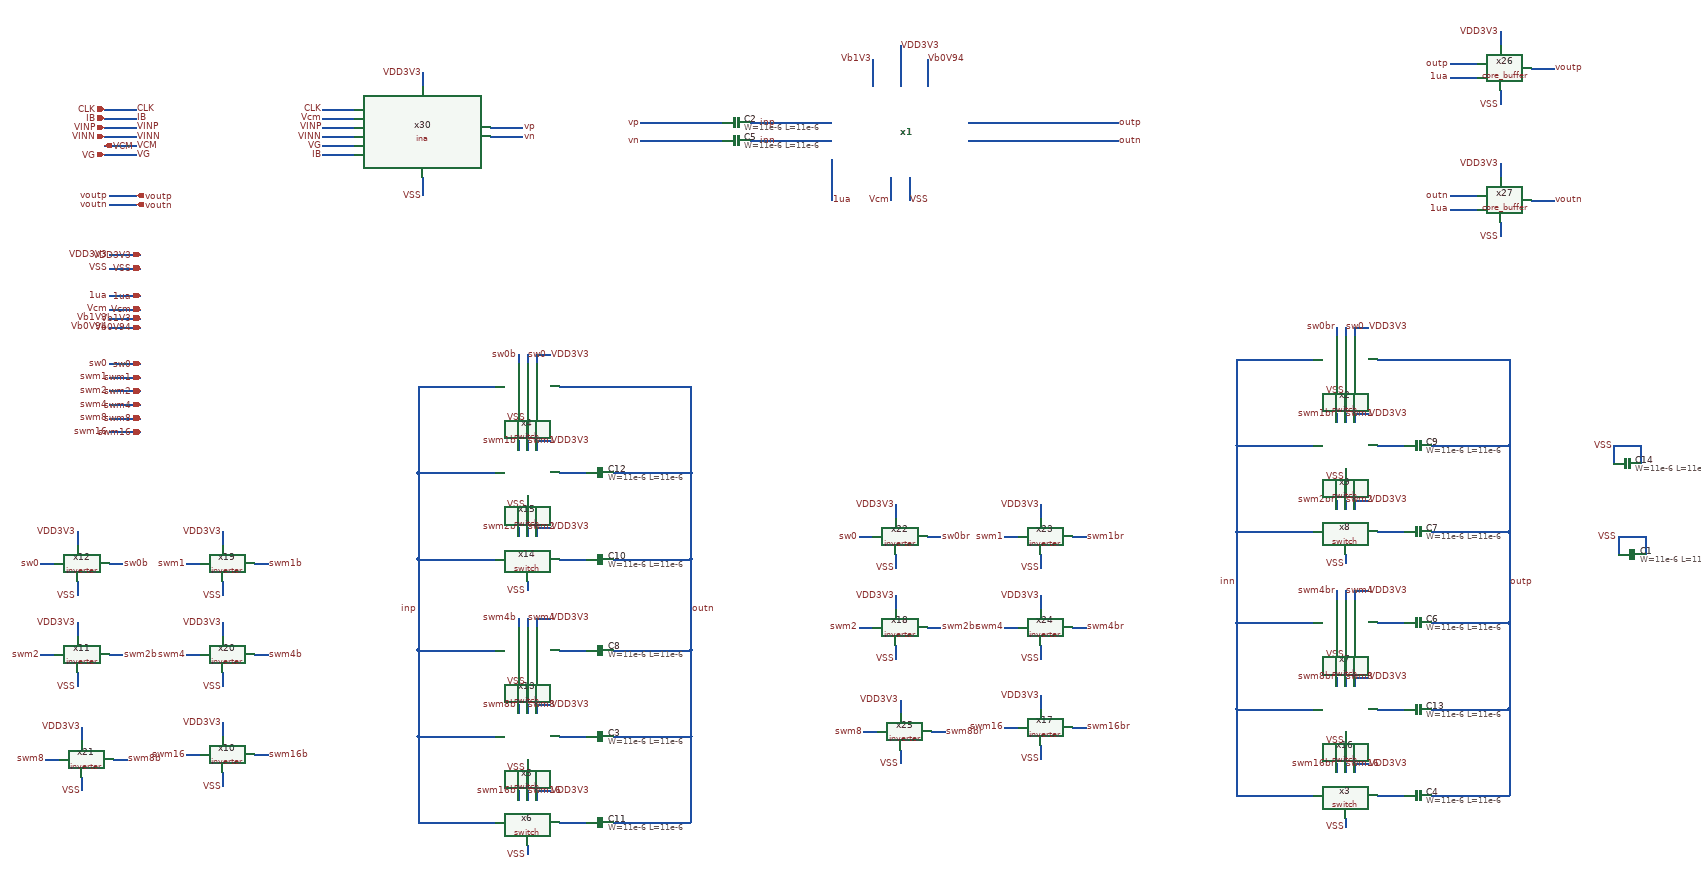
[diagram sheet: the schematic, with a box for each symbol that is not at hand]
v {xschem version=3.4.8RC file_version=1.3}
G {}
K {}
V {}
S {}
F {}
E {}
N 5160 -3050 5160 -3000 {lab=VSS}
N 4810 -3170 4990 -3170 {lab=inp}
N 4810 -3130 4990 -3130 {lab=inn}
N 5140 -3340 5140 -3250 {lab=VDD3V3}
N 5200 -3310 5200 -3250 {lab=Vb0V94}
N 5120 -3050 5120 -3000 {lab=Vcm}
N 5080 -3310 5080 -3250 {lab=Vb1V3}
N 4570 -3170 4750 -3170 {lab=vp}
N 4570 -3130 4750 -3130 {lab=vn}
N 4990 -3090 4990 -3000 {lab=1ua}
N 5290 -3130 5480 -3130 {lab=outn}
N 5290 -3170 5390 -3170 {lab=outp}
N 5390 -3170 5620 -3170 {lab=outp}
N 5480 -3130 5620 -3130 {lab=outn}
N 3400 -2990 3460 -2990 {lab=voutn}
N 3410 -2850 3470 -2850 {lab=VSS}
N 3400 -2850 3410 -2850 {lab=VSS}
N 3410 -2880 3470 -2880 {lab=VDD3V3}
N 3400 -2880 3410 -2880 {lab=VDD3V3}
N 3410 -2790 3470 -2790 {lab=1ua}
N 3400 -2790 3410 -2790 {lab=1ua}
N 3410 -2760 3470 -2760 {lab=Vcm}
N 3400 -2760 3410 -2760 {lab=Vcm}
N 3410 -2740 3470 -2740 {lab=Vb1V3}
N 3400 -2740 3410 -2740 {lab=Vb1V3}
N 3410 -2720 3470 -2720 {lab=Vb0V94}
N 3400 -2720 3410 -2720 {lab=Vb0V94}
N 3400 -3010 3460 -3010 {lab=voutp}
N 4300 -2660 4300 -2640 {lab=sw0b}
N 4320 -2660 4320 -2640 {lab=sw0}
N 4340 -2660 4340 -2640 {lab=VDD3V3}
N 4340 -2660 4370 -2660 {lab=VDD3V3}
N 4320 -2540 4320 -2520 {lab=VSS}
N 4300 -1890 4300 -1870 {lab=swm8b}
N 4320 -1890 4320 -1870 {lab=swm8}
N 4340 -1890 4340 -1870 {lab=VDD3V3}
N 4340 -1890 4370 -1890 {lab=VDD3V3}
N 4320 -1770 4320 -1750 {lab=VSS}
N 4300 -1700 4300 -1680 {lab=swm16b}
N 4320 -1700 4320 -1680 {lab=swm16}
N 4340 -1700 4340 -1680 {lab=VDD3V3}
N 4340 -1700 4370 -1700 {lab=VDD3V3}
N 4320 -1580 4320 -1560 {lab=VSS}
N 4390 -1630 4450 -1630 {lab=#net1}
N 4300 -2080 4300 -2060 {lab=swm4b}
N 4320 -2080 4320 -2060 {lab=swm4}
N 4340 -2080 4340 -2060 {lab=VDD3V3}
N 4340 -2080 4370 -2080 {lab=VDD3V3}
N 4320 -1960 4320 -1940 {lab=VSS}
N 4390 -2010 4450 -2010 {lab=#net2}
N 4300 -2280 4300 -2260 {lab=swm2b}
N 4320 -2280 4320 -2260 {lab=swm2}
N 4340 -2280 4340 -2260 {lab=VDD3V3}
N 4340 -2280 4370 -2280 {lab=VDD3V3}
N 4320 -2160 4320 -2140 {lab=VSS}
N 4390 -2210 4450 -2210 {lab=#net3}
N 4300 -2470 4300 -2450 {lab=swm1b}
N 4320 -2470 4320 -2450 {lab=swm1}
N 4340 -2470 4340 -2450 {lab=VDD3V3}
N 4340 -2470 4370 -2470 {lab=VDD3V3}
N 4320 -2350 4320 -2330 {lab=VSS}
N 4390 -2400 4450 -2400 {lab=#net4}
N 4080 -1630 4250 -1630 {lab=inp}
N 4510 -1630 4680 -1630 {lab=outn}
N 4510 -2010 4680 -2010 {lab=outn}
N 4080 -2010 4250 -2010 {lab=inp}
N 4510 -2210 4680 -2210 {lab=outn}
N 4080 -2210 4250 -2210 {lab=inp}
N 4510 -2400 4680 -2400 {lab=outn}
N 4080 -2400 4250 -2400 {lab=inp}
N 4080 -1820 4080 -1630 {lab=inp}
N 4080 -2010 4080 -1820 {lab=inp}
N 4080 -2210 4080 -2010 {lab=inp}
N 4080 -2400 4080 -2210 {lab=inp}
N 4680 -1820 4680 -1630 {lab=outn}
N 4680 -2010 4680 -1820 {lab=outn}
N 4680 -2210 4680 -2010 {lab=outn}
N 4680 -2400 4680 -2210 {lab=outn}
N 4080 -2590 4080 -2400 {lab=inp}
N 4080 -2590 4250 -2590 {lab=inp}
N 4680 -2590 4680 -2400 {lab=outn}
N 4390 -2590 4680 -2590 {lab=outn}
N 4080 -1820 4250 -1820 {lab=inp}
N 4390 -1820 4450 -1820 {lab=#net5}
N 4510 -1820 4680 -1820 {lab=outn}
N 3650 -1850 3650 -1820 {lab=VDD3V3}
N 3650 -1740 3650 -1710 {lab=VSS}
N 3570 -1780 3600 -1780 {lab=swm16}
N 3720 -1780 3750 -1780 {lab=swm16b}
N 3330 -2070 3330 -2040 {lab=VDD3V3}
N 3330 -1960 3330 -1930 {lab=VSS}
N 3250 -2000 3280 -2000 {lab=swm2}
N 3400 -2000 3430 -2000 {lab=swm2b}
N 3330 -2270 3330 -2240 {lab=VDD3V3}
N 3330 -2160 3330 -2130 {lab=VSS}
N 3250 -2200 3280 -2200 {lab=sw0}
N 3400 -2200 3430 -2200 {lab=sw0b}
N 3650 -2270 3650 -2240 {lab=VDD3V3}
N 3650 -2160 3650 -2130 {lab=VSS}
N 3570 -2200 3600 -2200 {lab=swm1}
N 3720 -2200 3750 -2200 {lab=swm1b}
N 3650 -2070 3650 -2040 {lab=VDD3V3}
N 3650 -1960 3650 -1930 {lab=VSS}
N 3570 -2000 3600 -2000 {lab=swm4}
N 3720 -2000 3750 -2000 {lab=swm4b}
N 3340 -1840 3340 -1810 {lab=VDD3V3}
N 3340 -1730 3340 -1700 {lab=VSS}
N 3260 -1770 3290 -1770 {lab=swm8}
N 3410 -1770 3440 -1770 {lab=swm8b}
N 6720 -2260 6720 -2220 {lab=VSS}
N 6720 -2260 6780 -2260 {lab=VSS}
N 6780 -2260 6780 -2220 {lab=VSS}
N 6100 -2720 6100 -2700 {lab=sw0br}
N 6120 -2720 6120 -2700 {lab=sw0}
N 6140 -2720 6140 -2700 {lab=VDD3V3}
N 6140 -2720 6170 -2720 {lab=VDD3V3}
N 6120 -2600 6120 -2580 {lab=VSS}
N 6100 -1950 6100 -1930 {lab=swm8br}
N 6120 -1950 6120 -1930 {lab=swm8}
N 6140 -1950 6140 -1930 {lab=VDD3V3}
N 6140 -1950 6170 -1950 {lab=VDD3V3}
N 6120 -1830 6120 -1810 {lab=VSS}
N 6100 -1760 6100 -1740 {lab=swm16br}
N 6120 -1760 6120 -1740 {lab=swm16}
N 6140 -1760 6140 -1740 {lab=VDD3V3}
N 6140 -1760 6170 -1760 {lab=VDD3V3}
N 6120 -1640 6120 -1620 {lab=VSS}
N 6190 -1690 6250 -1690 {lab=#net6}
N 6100 -2140 6100 -2120 {lab=swm4br}
N 6120 -2140 6120 -2120 {lab=swm4}
N 6140 -2140 6140 -2120 {lab=VDD3V3}
N 6140 -2140 6170 -2140 {lab=VDD3V3}
N 6120 -2020 6120 -2000 {lab=VSS}
N 6190 -2070 6250 -2070 {lab=#net7}
N 6100 -2340 6100 -2320 {lab=swm2br}
N 6120 -2340 6120 -2320 {lab=swm2}
N 6140 -2340 6140 -2320 {lab=VDD3V3}
N 6140 -2340 6170 -2340 {lab=VDD3V3}
N 6120 -2220 6120 -2200 {lab=VSS}
N 6190 -2270 6250 -2270 {lab=#net8}
N 6100 -2530 6100 -2510 {lab=swm1br}
N 6120 -2530 6120 -2510 {lab=swm1}
N 6140 -2530 6140 -2510 {lab=VDD3V3}
N 6140 -2530 6170 -2530 {lab=VDD3V3}
N 6120 -2410 6120 -2390 {lab=VSS}
N 6190 -2460 6250 -2460 {lab=#net9}
N 5880 -1690 6050 -1690 {lab=inn}
N 6310 -1690 6480 -1690 {lab=outp}
N 6310 -2070 6480 -2070 {lab=outp}
N 5880 -2070 6050 -2070 {lab=inn}
N 6310 -2270 6480 -2270 {lab=outp}
N 5880 -2270 6050 -2270 {lab=inn}
N 6310 -2460 6480 -2460 {lab=outp}
N 5880 -2460 6050 -2460 {lab=inn}
N 5880 -1880 5880 -1690 {lab=inn}
N 5880 -2070 5880 -1880 {lab=inn}
N 5880 -2270 5880 -2070 {lab=inn}
N 5880 -2460 5880 -2270 {lab=inn}
N 6480 -1880 6480 -1690 {lab=outp}
N 6480 -2070 6480 -1880 {lab=outp}
N 6480 -2270 6480 -2070 {lab=outp}
N 6480 -2460 6480 -2270 {lab=outp}
N 5880 -2650 5880 -2460 {lab=inn}
N 5880 -2650 6050 -2650 {lab=inn}
N 6480 -2650 6480 -2460 {lab=outp}
N 6190 -2650 6480 -2650 {lab=outp}
N 5880 -1880 6050 -1880 {lab=inn}
N 6190 -1880 6250 -1880 {lab=#net10}
N 6310 -1880 6480 -1880 {lab=outp}
N 5450 -1910 5450 -1880 {lab=VDD3V3}
N 5450 -1800 5450 -1770 {lab=VSS}
N 5370 -1840 5400 -1840 {lab=swm16}
N 5520 -1840 5550 -1840 {lab=swm16br}
N 5130 -2130 5130 -2100 {lab=VDD3V3}
N 5130 -2020 5130 -1990 {lab=VSS}
N 5050 -2060 5080 -2060 {lab=swm2}
N 5200 -2060 5230 -2060 {lab=swm2br}
N 5130 -2330 5130 -2300 {lab=VDD3V3}
N 5130 -2220 5130 -2190 {lab=VSS}
N 5050 -2260 5080 -2260 {lab=sw0}
N 5200 -2260 5230 -2260 {lab=sw0br}
N 5450 -2330 5450 -2300 {lab=VDD3V3}
N 5450 -2220 5450 -2190 {lab=VSS}
N 5370 -2260 5400 -2260 {lab=swm1}
N 5520 -2260 5550 -2260 {lab=swm1br}
N 5450 -2130 5450 -2100 {lab=VDD3V3}
N 5450 -2020 5450 -1990 {lab=VSS}
N 5370 -2060 5400 -2060 {lab=swm4}
N 5520 -2060 5550 -2060 {lab=swm4br}
N 5140 -1900 5140 -1870 {lab=VDD3V3}
N 5140 -1790 5140 -1760 {lab=VSS}
N 5060 -1830 5090 -1830 {lab=swm8}
N 5210 -1830 5240 -1830 {lab=swm8br}
N 6710 -2460 6710 -2420 {lab=VSS}
N 6710 -2460 6770 -2460 {lab=VSS}
N 6770 -2460 6770 -2420 {lab=VSS}
N 3410 -2640 3470 -2640 {lab=sw0}
N 3400 -2640 3410 -2640 {lab=sw0}
N 3410 -2610 3470 -2610 {lab=swm1}
N 3400 -2610 3410 -2610 {lab=swm1}
N 3410 -2580 3470 -2580 {lab=swm2}
N 3400 -2580 3410 -2580 {lab=swm2}
N 3410 -2550 3470 -2550 {lab=swm4}
N 3400 -2550 3410 -2550 {lab=swm4}
N 3410 -2520 3470 -2520 {lab=swm8}
N 3400 -2520 3410 -2520 {lab=swm8}
N 3410 -2490 3470 -2490 {lab=swm16}
N 3400 -2490 3410 -2490 {lab=swm16}
N 6350 -3270 6410 -3270 {lab=1ua}
N 6350 -3300 6410 -3300 {lab=outp}
N 6460 -3240 6460 -3210 {lab=VSS}
N 6460 -3370 6460 -3340 {lab=VDD3V3}
N 6530 -3290 6580 -3290 {lab=voutp}
N 6350 -2980 6410 -2980 {lab=1ua}
N 6350 -3010 6410 -3010 {lab=outn}
N 6460 -2950 6460 -2920 {lab=VSS}
N 6460 -3080 6460 -3050 {lab=VDD3V3}
N 6530 -3000 6580 -3000 {lab=voutn}
N 3390 -3200 3460 -3200 {lab=CLK}
N 3390 -3180 3460 -3180 {lab=IB}
N 3390 -3120 3460 -3120 {lab=VCM}
N 3390 -3100 3460 -3100 {lab=VG}
N 3390 -3140 3460 -3140 {lab=VINN}
N 3390 -3160 3460 -3160 {lab=VINP}
N 4240 -3160 4310 -3160 {lab=vp}
N 4240 -3140 4310 -3140 {lab=vn}
N 4090 -3050 4090 -3010 {lab=VSS}
N 3870 -3200 3940 -3200 {lab=CLK}
N 3870 -3180 3940 -3180 {lab=Vcm}
N 3870 -3160 3940 -3160 {lab=VINP}
N 3870 -3140 3940 -3140 {lab=VINN}
N 3870 -3120 3940 -3120 {lab=VG}
N 3870 -3100 3940 -3100 {lab=IB}
N 4090 -3280 4090 -3250 {lab=VDD3V3}
C {lab_pin.sym} 4990 -3000 0 1 {name=p2 sig_type=std_logic lab=1ua}
C {lab_wire.sym} 5160 -3000 0 1 {name=p3 sig_type=std_logic lab=VSS}
C {lab_pin.sym} 5140 -3340 0 1 {name=p4 sig_type=std_logic lab=VDD3V3}
C {lab_pin.sym} 5620 -3170 0 1 {name=p11 sig_type=std_logic lab=outp}
C {lab_pin.sym} 5620 -3130 0 1 {name=p13 sig_type=std_logic lab=outn}
C {lab_wire.sym} 4570 -3170 0 0 {name=p14 sig_type=std_logic lab=vp}
C {lab_wire.sym} 4570 -3130 0 0 {name=p16 sig_type=std_logic lab=vn}
C {lab_wire.sym} 5120 -3000 0 0 {name=p73 sig_type=std_logic lab=Vcm}
C {lab_pin.sym} 5080 -3310 0 0 {name=p77 sig_type=std_logic lab=Vb1V3}
C {lab_pin.sym} 5200 -3310 0 1 {name=p6 sig_type=std_logic lab=Vb0V94}
C {/foss/designs/core_pga/folded_cascode/folded_cascode_v3.sym} 5140 -3150 0 0 {name=x1}
C {symbols/cap_mim_2f0fF.sym} 4780 -3130 1 0 {name=C5
W=11e-6
L=11e-6
model=cap_mim_2f0fF
spiceprefix=X
m=16}
C {symbols/cap_mim_2f0fF.sym} 4780 -3170 1 1 {name=C2
W=11e-6
L=11e-6
model=cap_mim_2f0fF
spiceprefix=X
m=16}
C {lab_wire.sym} 4870 -3170 0 0 {name=p1 sig_type=std_logic lab=inp}
C {lab_wire.sym} 4870 -3130 0 0 {name=p5 sig_type=std_logic lab=inn}
C {opin.sym} 3460 -2990 0 0 {name=p46 lab=voutn}
C {lab_pin.sym} 3400 -2990 0 0 {name=p25 sig_type=std_logic lab=voutn}
C {iopin.sym} 3470 -2850 0 0 {name=p26 lab=VSS}
C {lab_wire.sym} 3400 -2850 0 0 {name=p49 sig_type=std_logic lab=VSS}
C {iopin.sym} 3470 -2880 0 0 {name=p50 lab=VDD3V3}
C {lab_pin.sym} 3400 -2880 0 0 {name=p27 sig_type=std_logic lab=VDD3V3}
C {iopin.sym} 3470 -2790 0 0 {name=p38 lab=1ua}
C {iopin.sym} 3470 -2760 0 0 {name=p41 lab=Vcm}
C {iopin.sym} 3470 -2740 0 0 {name=p43 lab=Vb1V3}
C {iopin.sym} 3470 -2720 0 0 {name=p45 lab=Vb0V94}
C {opin.sym} 3460 -3010 0 0 {name=p7 lab=voutp}
C {lab_pin.sym} 3400 -3010 0 0 {name=p8 sig_type=std_logic lab=voutp}
C {lab_pin.sym} 3400 -2790 0 0 {name=p17 sig_type=std_logic lab=1ua}
C {lab_wire.sym} 3400 -2760 0 0 {name=p18 sig_type=std_logic lab=Vcm}
C {lab_pin.sym} 3400 -2740 0 0 {name=p19 sig_type=std_logic lab=Vb1V3}
C {lab_pin.sym} 3400 -2720 0 0 {name=p20 sig_type=std_logic lab=Vb0V94}
C {lab_pin.sym} 4370 -2660 0 1 {name=p21 sig_type=std_logic lab=VDD3V3}
C {lab_wire.sym} 4320 -2520 0 0 {name=p22 sig_type=std_logic lab=VSS}
C {lab_wire.sym} 4320 -2660 0 1 {name=p31 sig_type=std_logic lab=sw0}
C {lab_wire.sym} 4300 -2660 0 0 {name=p33 sig_type=std_logic lab=sw0b}
C {/foss/designs/core_pga/switch/switch.sym} 4250 -2540 0 0 {name=x4}
C {lab_pin.sym} 4370 -1890 0 1 {name=p34 sig_type=std_logic lab=VDD3V3}
C {lab_wire.sym} 4320 -1750 0 0 {name=p35 sig_type=std_logic lab=VSS}
C {lab_pin.sym} 4370 -1700 0 1 {name=p40 sig_type=std_logic lab=VDD3V3}
C {lab_wire.sym} 4320 -1560 0 0 {name=p51 sig_type=std_logic lab=VSS}
C {/foss/designs/core_pga/switch/switch.sym} 4250 -1580 0 0 {name=x6}
C {lab_pin.sym} 4370 -2080 0 1 {name=p64 sig_type=std_logic lab=VDD3V3}
C {lab_wire.sym} 4320 -1940 0 0 {name=p78 sig_type=std_logic lab=VSS}
C {/foss/designs/core_pga/switch/switch.sym} 4250 -1960 0 0 {name=x13}
C {lab_wire.sym} 4300 -2280 0 0 {name=p83 sig_type=std_logic lab=swm2b}
C {lab_wire.sym} 4320 -2140 0 0 {name=p85 sig_type=std_logic lab=VSS}
C {/foss/designs/core_pga/switch/switch.sym} 4250 -2160 0 0 {name=x14}
C {lab_wire.sym} 4320 -2470 0 1 {name=p86 sig_type=std_logic lab=swm1}
C {lab_wire.sym} 4300 -2470 0 0 {name=p87 sig_type=std_logic lab=swm1b}
C {lab_pin.sym} 4370 -2470 0 1 {name=p88 sig_type=std_logic lab=VDD3V3}
C {lab_wire.sym} 4320 -2330 0 0 {name=p89 sig_type=std_logic lab=VSS}
C {/foss/designs/core_pga/switch/switch.sym} 4250 -2350 0 0 {name=x15}
C {symbols/cap_mim_2f0fF.sym} 4480 -1630 1 0 {name=C11
W=11e-6
L=11e-6
model=cap_mim_2f0fF
spiceprefix=X
m=16}
C {symbols/cap_mim_2f0fF.sym} 4480 -2010 1 0 {name=C8
W=11e-6
L=11e-6
model=cap_mim_2f0fF
spiceprefix=X
m=4}
C {symbols/cap_mim_2f0fF.sym} 4480 -2210 1 0 {name=C10
W=11e-6
L=11e-6
model=cap_mim_2f0fF
spiceprefix=X
m=2}
C {symbols/cap_mim_2f0fF.sym} 4480 -2400 1 0 {name=C12
W=11e-6
L=11e-6
model=cap_mim_2f0fF
spiceprefix=X
m=1}
C {symbols/cap_mim_2f0fF.sym} 4480 -1820 1 0 {name=C3
W=11e-6
L=11e-6
model=cap_mim_2f0fF
spiceprefix=X
m=8}
C {/foss/designs/core_pga/switch/switch.sym} 4250 -1770 0 0 {name=x5}
C {lab_pin.sym} 3650 -1850 0 0 {name=p47 sig_type=std_logic lab=VDD3V3}
C {lab_wire.sym} 3650 -1710 0 0 {name=p48 sig_type=std_logic lab=VSS}
C {/foss/designs/core_pga/inverter/inverter.sym} 3600 -1740 0 0 {name=x10}
C {lab_pin.sym} 3330 -2070 0 0 {name=p63 sig_type=std_logic lab=VDD3V3}
C {lab_wire.sym} 3330 -1930 0 0 {name=p69 sig_type=std_logic lab=VSS}
C {/foss/designs/core_pga/inverter/inverter.sym} 3280 -1960 0 0 {name=x11}
C {lab_pin.sym} 3330 -2270 0 0 {name=p79 sig_type=std_logic lab=VDD3V3}
C {lab_wire.sym} 3330 -2130 0 0 {name=p81 sig_type=std_logic lab=VSS}
C {/foss/designs/core_pga/inverter/inverter.sym} 3280 -2160 0 0 {name=x12}
C {lab_pin.sym} 3650 -2270 0 0 {name=p104 sig_type=std_logic lab=VDD3V3}
C {lab_wire.sym} 3650 -2130 0 0 {name=p105 sig_type=std_logic lab=VSS}
C {/foss/designs/core_pga/inverter/inverter.sym} 3600 -2160 0 0 {name=x19}
C {lab_pin.sym} 3650 -2070 0 0 {name=p108 sig_type=std_logic lab=VDD3V3}
C {lab_wire.sym} 3650 -1930 0 0 {name=p109 sig_type=std_logic lab=VSS}
C {/foss/designs/core_pga/inverter/inverter.sym} 3600 -1960 0 0 {name=x20}
C {lab_pin.sym} 3340 -1840 0 0 {name=p112 sig_type=std_logic lab=VDD3V3}
C {lab_wire.sym} 3340 -1700 0 0 {name=p113 sig_type=std_logic lab=VSS}
C {/foss/designs/core_pga/inverter/inverter.sym} 3290 -1730 0 0 {name=x21}
C {lab_wire.sym} 3250 -2200 0 0 {name=p23 sig_type=std_logic lab=sw0}
C {lab_wire.sym} 3430 -2200 0 1 {name=p24 sig_type=std_logic lab=sw0b}
C {lab_wire.sym} 4320 -1700 0 1 {name=p32 sig_type=std_logic lab=swm16}
C {lab_wire.sym} 4300 -1700 0 0 {name=p37 sig_type=std_logic lab=swm16b}
C {lab_wire.sym} 3570 -2200 0 0 {name=p39 sig_type=std_logic lab=swm1}
C {lab_wire.sym} 3750 -2200 0 1 {name=p42 sig_type=std_logic lab=swm1b}
C {lab_wire.sym} 3250 -2000 0 0 {name=p44 sig_type=std_logic lab=swm2}
C {lab_wire.sym} 3430 -2000 0 1 {name=p52 sig_type=std_logic lab=swm2b}
C {lab_pin.sym} 4370 -2280 0 1 {name=p53 sig_type=std_logic lab=VDD3V3}
C {lab_wire.sym} 4320 -2280 0 1 {name=p54 sig_type=std_logic lab=swm2}
C {lab_wire.sym} 4300 -2080 0 0 {name=p55 sig_type=std_logic lab=swm4b}
C {lab_wire.sym} 4320 -2080 0 1 {name=p56 sig_type=std_logic lab=swm4}
C {lab_wire.sym} 3570 -2000 0 0 {name=p57 sig_type=std_logic lab=swm4}
C {lab_wire.sym} 3750 -2000 0 1 {name=p58 sig_type=std_logic lab=swm4b}
C {lab_wire.sym} 3260 -1770 0 0 {name=p59 sig_type=std_logic lab=swm8}
C {lab_wire.sym} 3440 -1770 0 1 {name=p60 sig_type=std_logic lab=swm8b}
C {lab_wire.sym} 4300 -1890 0 0 {name=p61 sig_type=std_logic lab=swm8b}
C {lab_wire.sym} 4320 -1890 0 1 {name=p62 sig_type=std_logic lab=swm8}
C {lab_wire.sym} 3570 -1780 0 0 {name=p65 sig_type=std_logic lab=swm16}
C {lab_wire.sym} 3750 -1780 0 1 {name=p66 sig_type=std_logic lab=swm16b}
C {lab_pin.sym} 4080 -2100 0 0 {name=p67 sig_type=std_logic lab=inp}
C {lab_wire.sym} 4680 -2100 0 1 {name=p68 sig_type=std_logic lab=outn}
C {symbols/cap_mim_2f0fF.sym} 6750 -2220 1 0 {name=C1
W=11e-6
L=11e-6
model=cap_mim_2f0fF
spiceprefix=X
m=1}
C {lab_wire.sym} 6720 -2260 0 0 {name=p70 sig_type=std_logic lab=VSS}
C {lab_pin.sym} 6170 -2720 0 1 {name=p71 sig_type=std_logic lab=VDD3V3}
C {lab_wire.sym} 6120 -2580 0 0 {name=p72 sig_type=std_logic lab=VSS}
C {lab_wire.sym} 6120 -2720 0 1 {name=p74 sig_type=std_logic lab=sw0}
C {lab_wire.sym} 6100 -2720 0 0 {name=p75 sig_type=std_logic lab=sw0br}
C {/foss/designs/core_pga/switch/switch.sym} 6050 -2600 0 0 {name=x2}
C {lab_pin.sym} 6170 -1950 0 1 {name=p76 sig_type=std_logic lab=VDD3V3}
C {lab_wire.sym} 6120 -1810 0 0 {name=p80 sig_type=std_logic lab=VSS}
C {lab_pin.sym} 6170 -1760 0 1 {name=p82 sig_type=std_logic lab=VDD3V3}
C {lab_wire.sym} 6120 -1620 0 0 {name=p84 sig_type=std_logic lab=VSS}
C {/foss/designs/core_pga/switch/switch.sym} 6050 -1640 0 0 {name=x3}
C {lab_pin.sym} 6170 -2140 0 1 {name=p90 sig_type=std_logic lab=VDD3V3}
C {lab_wire.sym} 6120 -2000 0 0 {name=p91 sig_type=std_logic lab=VSS}
C {/foss/designs/core_pga/switch/switch.sym} 6050 -2020 0 0 {name=x7}
C {lab_wire.sym} 6100 -2340 0 0 {name=p92 sig_type=std_logic lab=swm2br}
C {lab_wire.sym} 6120 -2200 0 0 {name=p93 sig_type=std_logic lab=VSS}
C {/foss/designs/core_pga/switch/switch.sym} 6050 -2220 0 0 {name=x8}
C {lab_wire.sym} 6120 -2530 0 1 {name=p94 sig_type=std_logic lab=swm1}
C {lab_wire.sym} 6100 -2530 0 0 {name=p95 sig_type=std_logic lab=swm1br}
C {lab_pin.sym} 6170 -2530 0 1 {name=p96 sig_type=std_logic lab=VDD3V3}
C {lab_wire.sym} 6120 -2390 0 0 {name=p97 sig_type=std_logic lab=VSS}
C {/foss/designs/core_pga/switch/switch.sym} 6050 -2410 0 0 {name=x9}
C {symbols/cap_mim_2f0fF.sym} 6280 -1690 1 0 {name=C4
W=11e-6
L=11e-6
model=cap_mim_2f0fF
spiceprefix=X
m=16}
C {symbols/cap_mim_2f0fF.sym} 6280 -2070 1 0 {name=C6
W=11e-6
L=11e-6
model=cap_mim_2f0fF
spiceprefix=X
m=4}
C {symbols/cap_mim_2f0fF.sym} 6280 -2270 1 0 {name=C7
W=11e-6
L=11e-6
model=cap_mim_2f0fF
spiceprefix=X
m=2}
C {symbols/cap_mim_2f0fF.sym} 6280 -2460 1 0 {name=C9
W=11e-6
L=11e-6
model=cap_mim_2f0fF
spiceprefix=X
m=1}
C {symbols/cap_mim_2f0fF.sym} 6280 -1880 1 0 {name=C13
W=11e-6
L=11e-6
model=cap_mim_2f0fF
spiceprefix=X
m=8}
C {/foss/designs/core_pga/switch/switch.sym} 6050 -1830 0 0 {name=x16}
C {lab_pin.sym} 5450 -1910 0 0 {name=p98 sig_type=std_logic lab=VDD3V3}
C {lab_wire.sym} 5450 -1770 0 0 {name=p99 sig_type=std_logic lab=VSS}
C {/foss/designs/core_pga/inverter/inverter.sym} 5400 -1800 0 0 {name=x17}
C {lab_pin.sym} 5130 -2130 0 0 {name=p100 sig_type=std_logic lab=VDD3V3}
C {lab_wire.sym} 5130 -1990 0 0 {name=p101 sig_type=std_logic lab=VSS}
C {/foss/designs/core_pga/inverter/inverter.sym} 5080 -2020 0 0 {name=x18}
C {lab_pin.sym} 5130 -2330 0 0 {name=p102 sig_type=std_logic lab=VDD3V3}
C {lab_wire.sym} 5130 -2190 0 0 {name=p103 sig_type=std_logic lab=VSS}
C {/foss/designs/core_pga/inverter/inverter.sym} 5080 -2220 0 0 {name=x22}
C {lab_pin.sym} 5450 -2330 0 0 {name=p106 sig_type=std_logic lab=VDD3V3}
C {lab_wire.sym} 5450 -2190 0 0 {name=p107 sig_type=std_logic lab=VSS}
C {/foss/designs/core_pga/inverter/inverter.sym} 5400 -2220 0 0 {name=x23}
C {lab_pin.sym} 5450 -2130 0 0 {name=p110 sig_type=std_logic lab=VDD3V3}
C {lab_wire.sym} 5450 -1990 0 0 {name=p111 sig_type=std_logic lab=VSS}
C {/foss/designs/core_pga/inverter/inverter.sym} 5400 -2020 0 0 {name=x24}
C {lab_pin.sym} 5140 -1900 0 0 {name=p114 sig_type=std_logic lab=VDD3V3}
C {lab_wire.sym} 5140 -1760 0 0 {name=p115 sig_type=std_logic lab=VSS}
C {/foss/designs/core_pga/inverter/inverter.sym} 5090 -1790 0 0 {name=x25}
C {lab_wire.sym} 5050 -2260 0 0 {name=p116 sig_type=std_logic lab=sw0}
C {lab_wire.sym} 5230 -2260 0 1 {name=p117 sig_type=std_logic lab=sw0br}
C {lab_wire.sym} 6120 -1760 0 1 {name=p118 sig_type=std_logic lab=swm16}
C {lab_wire.sym} 6100 -1760 0 0 {name=p119 sig_type=std_logic lab=swm16br}
C {lab_wire.sym} 5370 -2260 0 0 {name=p120 sig_type=std_logic lab=swm1}
C {lab_wire.sym} 5550 -2260 0 1 {name=p121 sig_type=std_logic lab=swm1br}
C {lab_wire.sym} 5050 -2060 0 0 {name=p122 sig_type=std_logic lab=swm2}
C {lab_wire.sym} 5230 -2060 0 1 {name=p123 sig_type=std_logic lab=swm2br}
C {lab_pin.sym} 6170 -2340 0 1 {name=p124 sig_type=std_logic lab=VDD3V3}
C {lab_wire.sym} 6120 -2340 0 1 {name=p125 sig_type=std_logic lab=swm2}
C {lab_wire.sym} 6100 -2140 0 0 {name=p126 sig_type=std_logic lab=swm4br}
C {lab_wire.sym} 6120 -2140 0 1 {name=p127 sig_type=std_logic lab=swm4}
C {lab_wire.sym} 5370 -2060 0 0 {name=p128 sig_type=std_logic lab=swm4}
C {lab_wire.sym} 5550 -2060 0 1 {name=p129 sig_type=std_logic lab=swm4br}
C {lab_wire.sym} 5060 -1830 0 0 {name=p130 sig_type=std_logic lab=swm8}
C {lab_wire.sym} 5240 -1830 0 1 {name=p131 sig_type=std_logic lab=swm8br}
C {lab_wire.sym} 6100 -1950 0 0 {name=p132 sig_type=std_logic lab=swm8br}
C {lab_wire.sym} 6120 -1950 0 1 {name=p133 sig_type=std_logic lab=swm8}
C {lab_wire.sym} 5370 -1840 0 0 {name=p134 sig_type=std_logic lab=swm16}
C {lab_wire.sym} 5550 -1840 0 1 {name=p135 sig_type=std_logic lab=swm16br}
C {lab_pin.sym} 5880 -2160 0 0 {name=p136 sig_type=std_logic lab=inn}
C {lab_wire.sym} 6480 -2160 0 1 {name=p137 sig_type=std_logic lab=outp}
C {symbols/cap_mim_2f0fF.sym} 6740 -2420 1 0 {name=C14
W=11e-6
L=11e-6
model=cap_mim_2f0fF
spiceprefix=X
m=1}
C {lab_wire.sym} 6710 -2460 0 0 {name=p138 sig_type=std_logic lab=VSS}
C {iopin.sym} 3470 -2640 0 0 {name=p147 lab=sw0}
C {iopin.sym} 3470 -2610 0 0 {name=p148 lab=swm1}
C {iopin.sym} 3470 -2580 0 0 {name=p149 lab=swm2}
C {iopin.sym} 3470 -2550 0 0 {name=p150 lab=swm4}
C {iopin.sym} 3470 -2520 0 0 {name=p151 lab=swm8}
C {iopin.sym} 3470 -2490 0 0 {name=p152 lab=swm16}
C {lab_wire.sym} 3400 -2640 0 0 {name=p153 sig_type=std_logic lab=sw0}
C {lab_wire.sym} 3400 -2610 0 0 {name=p154 sig_type=std_logic lab=swm1}
C {lab_wire.sym} 3400 -2580 0 0 {name=p155 sig_type=std_logic lab=swm2}
C {lab_wire.sym} 3400 -2550 0 0 {name=p156 sig_type=std_logic lab=swm4}
C {lab_wire.sym} 3400 -2520 0 0 {name=p157 sig_type=std_logic lab=swm8}
C {lab_wire.sym} 3400 -2490 0 0 {name=p158 sig_type=std_logic lab=swm16}
C {lab_wire.sym} 6460 -3210 0 0 {name=p140 sig_type=std_logic lab=VSS}
C {lab_pin.sym} 6460 -3370 0 0 {name=p141 sig_type=std_logic lab=VDD3V3}
C {lab_pin.sym} 6580 -3000 0 1 {name=p142 sig_type=std_logic lab=voutn}
C {lab_pin.sym} 6580 -3290 0 1 {name=p143 sig_type=std_logic lab=voutp}
C {lab_pin.sym} 6350 -3270 0 0 {name=p144 sig_type=std_logic lab=1ua}
C {lab_pin.sym} 6350 -3010 0 0 {name=p145 sig_type=std_logic lab=outn}
C {lab_pin.sym} 6350 -3300 0 0 {name=p146 sig_type=std_logic lab=outp}
C {lab_wire.sym} 6460 -2920 0 0 {name=p159 sig_type=std_logic lab=VSS}
C {lab_pin.sym} 6460 -3080 0 0 {name=p160 sig_type=std_logic lab=VDD3V3}
C {lab_pin.sym} 6350 -2980 0 0 {name=p161 sig_type=std_logic lab=1ua}
C {/foss/designs/core_pga/buffer/core_buffer.sym} 6410 -3240 0 0 {name=x26}
C {/foss/designs/core_pga/buffer/core_buffer.sym} 6410 -2950 0 0 {name=x27}
C {ipin.sym} 3390 -3200 0 0 {name=p10 lab=CLK}
C {lab_wire.sym} 3460 -3200 0 1 {name=p28 sig_type=std_logic lab=CLK}
C {ipin.sym} 3390 -3180 0 0 {name=p139 lab=IB}
C {lab_wire.sym} 3460 -3180 0 1 {name=p166 sig_type=std_logic lab=IB}
C {ipin.sym} 3390 -3160 0 0 {name=p163 lab=VINP}
C {ipin.sym} 3390 -3140 0 0 {name=p169 lab=VINN}
C {ipin.sym} 3390 -3120 2 1 {name=p170 lab=VCM}
C {ipin.sym} 3390 -3100 0 0 {name=p171 lab=VG}
C {lab_wire.sym} 3460 -3160 0 1 {name=p172 sig_type=std_logic lab=VINP}
C {lab_wire.sym} 3460 -3140 0 1 {name=p173 sig_type=std_logic lab=VINN}
C {lab_wire.sym} 3460 -3120 0 1 {name=p174 sig_type=std_logic lab=VCM}
C {lab_wire.sym} 3460 -3100 0 1 {name=p175 sig_type=std_logic lab=VG}
C {/foss/designs/core_ina/ina.sym} 4090 -3150 0 0 {name=x30}
C {lab_wire.sym} 4310 -3160 0 1 {name=p30 sig_type=std_logic lab=vp}
C {lab_wire.sym} 4310 -3140 0 1 {name=p162 sig_type=std_logic lab=vn}
C {lab_wire.sym} 4090 -3010 0 0 {name=p164 sig_type=std_logic lab=VSS}
C {lab_wire.sym} 3870 -3160 0 0 {name=p179 sig_type=std_logic lab=VINP}
C {lab_wire.sym} 3870 -3140 0 0 {name=p180 sig_type=std_logic lab=VINN}
C {lab_wire.sym} 3870 -3180 0 0 {name=p181 sig_type=std_logic lab=Vcm}
C {lab_wire.sym} 3870 -3120 0 0 {name=p182 sig_type=std_logic lab=VG}
C {lab_wire.sym} 3870 -3200 0 0 {name=p183 sig_type=std_logic lab=CLK}
C {lab_wire.sym} 3870 -3100 0 0 {name=p184 sig_type=std_logic lab=IB}
C {lab_pin.sym} 4090 -3280 0 0 {name=p185 sig_type=std_logic lab=VDD3V3}
